VERSION 5.7 ;
  NOWIREEXTENSIONATPIN ON ;
  DIVIDERCHAR "/" ;
  BUSBITCHARS "[]" ;
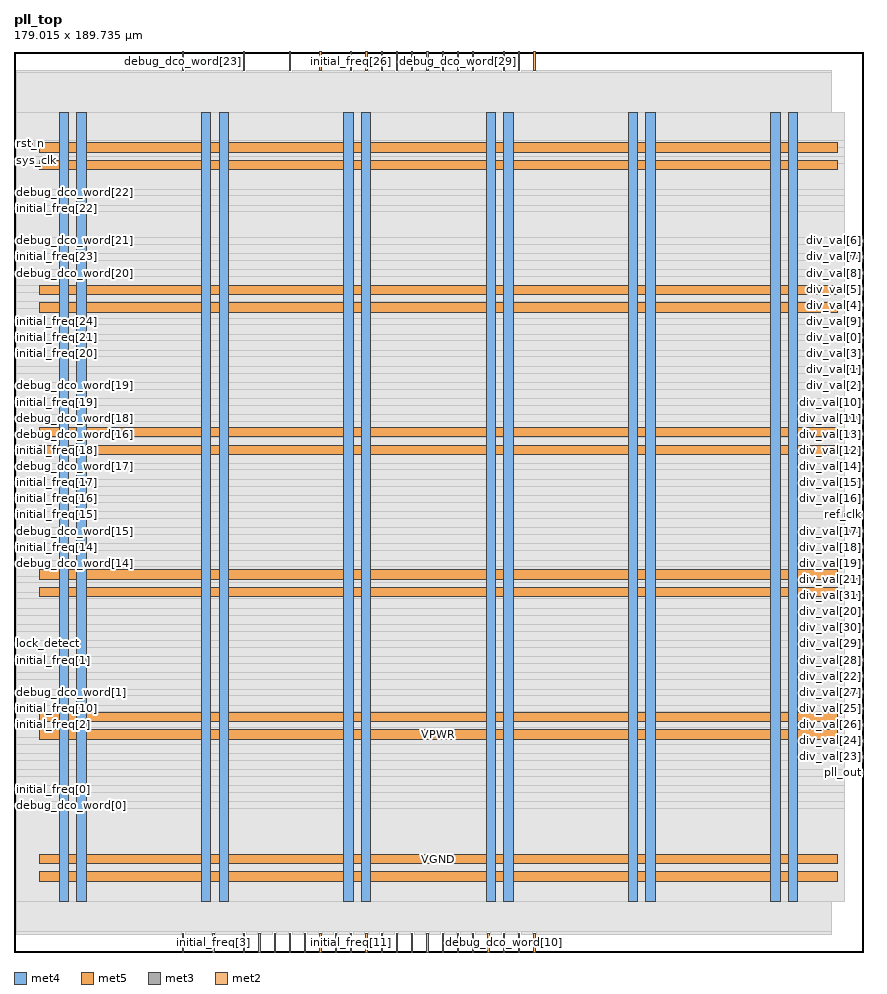
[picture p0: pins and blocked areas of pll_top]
MACRO pll_top
  CLASS BLOCK ;
  FOREIGN pll_top ;
  ORIGIN 0.000 0.000 ;
  SIZE 179.015 BY 189.735 ;
  PIN VGND
    DIRECTION INOUT ;
    USE GROUND ;
    PORT
      LAYER met4 ;
        RECT 13.220 10.640 15.220 177.040 ;
    END
    PORT
      LAYER met4 ;
        RECT 43.220 10.640 45.220 177.040 ;
    END
    PORT
      LAYER met4 ;
        RECT 73.220 10.640 75.220 177.040 ;
    END
    PORT
      LAYER met4 ;
        RECT 103.220 10.640 105.220 177.040 ;
    END
    PORT
      LAYER met4 ;
        RECT 133.220 10.640 135.220 177.040 ;
    END
    PORT
      LAYER met4 ;
        RECT 163.220 10.640 165.220 177.040 ;
    END
    PORT
      LAYER met5 ;
        RECT 5.280 18.580 173.660 20.580 ;
    END
    PORT
      LAYER met5 ;
        RECT 5.280 48.580 173.660 50.580 ;
    END
    PORT
      LAYER met5 ;
        RECT 5.280 78.580 173.660 80.580 ;
    END
    PORT
      LAYER met5 ;
        RECT 5.280 108.580 173.660 110.580 ;
    END
    PORT
      LAYER met5 ;
        RECT 5.280 138.580 173.660 140.580 ;
    END
    PORT
      LAYER met5 ;
        RECT 5.280 168.580 173.660 170.580 ;
    END
  END VGND
  PIN VPWR
    DIRECTION INOUT ;
    USE POWER ;
    PORT
      LAYER met4 ;
        RECT 9.520 10.640 11.520 177.040 ;
    END
    PORT
      LAYER met4 ;
        RECT 39.520 10.640 41.520 177.040 ;
    END
    PORT
      LAYER met4 ;
        RECT 69.520 10.640 71.520 177.040 ;
    END
    PORT
      LAYER met4 ;
        RECT 99.520 10.640 101.520 177.040 ;
    END
    PORT
      LAYER met4 ;
        RECT 129.520 10.640 131.520 177.040 ;
    END
    PORT
      LAYER met4 ;
        RECT 159.520 10.640 161.520 177.040 ;
    END
    PORT
      LAYER met5 ;
        RECT 5.280 14.880 173.660 16.880 ;
    END
    PORT
      LAYER met5 ;
        RECT 5.280 44.880 173.660 46.880 ;
    END
    PORT
      LAYER met5 ;
        RECT 5.280 74.880 173.660 76.880 ;
    END
    PORT
      LAYER met5 ;
        RECT 5.280 104.880 173.660 106.880 ;
    END
    PORT
      LAYER met5 ;
        RECT 5.280 134.880 173.660 136.880 ;
    END
    PORT
      LAYER met5 ;
        RECT 5.280 164.880 173.660 166.880 ;
    END
  END VPWR
  PIN debug_dco_word[0]
    DIRECTION OUTPUT ;
    USE SIGNAL ;
    ANTENNADIFFAREA 0.445500 ;
    PORT
      LAYER met3 ;
        RECT 0.000 30.640 4.000 31.240 ;
    END
  END debug_dco_word[0]
  PIN debug_dco_word[10]
    DIRECTION OUTPUT ;
    USE SIGNAL ;
    ANTENNADIFFAREA 0.445500 ;
    PORT
      LAYER met2 ;
        RECT 103.130 0.000 103.410 4.000 ;
    END
  END debug_dco_word[10]
  PIN debug_dco_word[11]
    DIRECTION OUTPUT ;
    USE SIGNAL ;
    ANTENNADIFFAREA 0.445500 ;
    PORT
      LAYER met2 ;
        RECT 67.710 0.000 67.990 4.000 ;
    END
  END debug_dco_word[11]
  PIN debug_dco_word[12]
    DIRECTION OUTPUT ;
    USE SIGNAL ;
    ANTENNADIFFAREA 0.445500 ;
    PORT
      LAYER met2 ;
        RECT 96.690 0.000 96.970 4.000 ;
    END
  END debug_dco_word[12]
  PIN debug_dco_word[13]
    DIRECTION OUTPUT ;
    USE SIGNAL ;
    ANTENNADIFFAREA 0.445500 ;
    PORT
      LAYER met2 ;
        RECT 87.030 0.000 87.310 4.000 ;
    END
  END debug_dco_word[13]
  PIN debug_dco_word[14]
    DIRECTION OUTPUT ;
    USE SIGNAL ;
    ANTENNADIFFAREA 0.445500 ;
    PORT
      LAYER met3 ;
        RECT 0.000 81.640 4.000 82.240 ;
    END
  END debug_dco_word[14]
  PIN debug_dco_word[15]
    DIRECTION OUTPUT ;
    USE SIGNAL ;
    ANTENNADIFFAREA 0.445500 ;
    PORT
      LAYER met3 ;
        RECT 0.000 88.440 4.000 89.040 ;
    END
  END debug_dco_word[15]
  PIN debug_dco_word[16]
    DIRECTION OUTPUT ;
    USE SIGNAL ;
    ANTENNADIFFAREA 0.445500 ;
    PORT
      LAYER met3 ;
        RECT 0.000 108.840 4.000 109.440 ;
    END
  END debug_dco_word[16]
  PIN debug_dco_word[17]
    DIRECTION OUTPUT ;
    USE SIGNAL ;
    ANTENNADIFFAREA 0.445500 ;
    PORT
      LAYER met3 ;
        RECT 0.000 102.040 4.000 102.640 ;
    END
  END debug_dco_word[17]
  PIN debug_dco_word[18]
    DIRECTION OUTPUT ;
    USE SIGNAL ;
    ANTENNADIFFAREA 0.445500 ;
    PORT
      LAYER met3 ;
        RECT 0.000 112.240 4.000 112.840 ;
    END
  END debug_dco_word[18]
  PIN debug_dco_word[19]
    DIRECTION OUTPUT ;
    USE SIGNAL ;
    ANTENNADIFFAREA 0.445500 ;
    PORT
      LAYER met3 ;
        RECT 0.000 119.040 4.000 119.640 ;
    END
  END debug_dco_word[19]
  PIN debug_dco_word[1]
    DIRECTION OUTPUT ;
    USE SIGNAL ;
    ANTENNADIFFAREA 0.445500 ;
    PORT
      LAYER met3 ;
        RECT 0.000 54.440 4.000 55.040 ;
    END
  END debug_dco_word[1]
  PIN debug_dco_word[20]
    DIRECTION OUTPUT ;
    USE SIGNAL ;
    ANTENNADIFFAREA 0.445500 ;
    PORT
      LAYER met3 ;
        RECT 0.000 142.840 4.000 143.440 ;
    END
  END debug_dco_word[20]
  PIN debug_dco_word[21]
    DIRECTION OUTPUT ;
    USE SIGNAL ;
    ANTENNADIFFAREA 0.445500 ;
    PORT
      LAYER met3 ;
        RECT 0.000 149.640 4.000 150.240 ;
    END
  END debug_dco_word[21]
  PIN debug_dco_word[22]
    DIRECTION OUTPUT ;
    USE SIGNAL ;
    ANTENNADIFFAREA 0.445500 ;
    PORT
      LAYER met3 ;
        RECT 0.000 159.840 4.000 160.440 ;
    END
  END debug_dco_word[22]
  PIN debug_dco_word[23]
    DIRECTION OUTPUT ;
    USE SIGNAL ;
    ANTENNADIFFAREA 0.445500 ;
    PORT
      LAYER met2 ;
        RECT 35.510 185.735 35.790 189.735 ;
    END
  END debug_dco_word[23]
  PIN debug_dco_word[24]
    DIRECTION OUTPUT ;
    USE SIGNAL ;
    ANTENNADIFFAREA 0.445500 ;
    PORT
      LAYER met2 ;
        RECT 48.390 185.735 48.670 189.735 ;
    END
  END debug_dco_word[24]
  PIN debug_dco_word[25]
    DIRECTION OUTPUT ;
    USE SIGNAL ;
    ANTENNADIFFAREA 0.445500 ;
    PORT
      LAYER met2 ;
        RECT 64.490 185.735 64.770 189.735 ;
    END
  END debug_dco_word[25]
  PIN debug_dco_word[26]
    DIRECTION OUTPUT ;
    USE SIGNAL ;
    ANTENNADIFFAREA 0.445500 ;
    PORT
      LAYER met2 ;
        RECT 77.370 185.735 77.650 189.735 ;
    END
  END debug_dco_word[26]
  PIN debug_dco_word[27]
    DIRECTION OUTPUT ;
    USE SIGNAL ;
    ANTENNADIFFAREA 0.445500 ;
    PORT
      LAYER met2 ;
        RECT 80.590 185.735 80.870 189.735 ;
    END
  END debug_dco_word[27]
  PIN debug_dco_word[28]
    DIRECTION OUTPUT ;
    USE SIGNAL ;
    ANTENNADIFFAREA 0.445500 ;
    PORT
      LAYER met2 ;
        RECT 90.250 185.735 90.530 189.735 ;
    END
  END debug_dco_word[28]
  PIN debug_dco_word[29]
    DIRECTION OUTPUT ;
    USE SIGNAL ;
    ANTENNADIFFAREA 0.445500 ;
    PORT
      LAYER met2 ;
        RECT 93.470 185.735 93.750 189.735 ;
    END
  END debug_dco_word[29]
  PIN debug_dco_word[2]
    DIRECTION OUTPUT ;
    USE SIGNAL ;
    ANTENNADIFFAREA 0.445500 ;
    PORT
      LAYER met2 ;
        RECT 35.510 0.000 35.790 4.000 ;
    END
  END debug_dco_word[2]
  PIN debug_dco_word[30]
    DIRECTION OUTPUT ;
    USE SIGNAL ;
    ANTENNADIFFAREA 0.445500 ;
    PORT
      LAYER met2 ;
        RECT 106.350 185.735 106.630 189.735 ;
    END
  END debug_dco_word[30]
  PIN debug_dco_word[31]
    DIRECTION OUTPUT ;
    USE SIGNAL ;
    ANTENNADIFFAREA 0.445500 ;
    PORT
      LAYER met2 ;
        RECT 109.570 185.735 109.850 189.735 ;
    END
  END debug_dco_word[31]
  PIN debug_dco_word[3]
    DIRECTION OUTPUT ;
    USE SIGNAL ;
    ANTENNADIFFAREA 0.445500 ;
    PORT
      LAYER met2 ;
        RECT 48.390 0.000 48.670 4.000 ;
    END
  END debug_dco_word[3]
  PIN debug_dco_word[4]
    DIRECTION OUTPUT ;
    USE SIGNAL ;
    ANTENNADIFFAREA 0.445500 ;
    PORT
      LAYER met2 ;
        RECT 51.610 0.000 51.890 4.000 ;
    END
  END debug_dco_word[4]
  PIN debug_dco_word[5]
    DIRECTION OUTPUT ;
    USE SIGNAL ;
    ANTENNADIFFAREA 0.445500 ;
    PORT
      LAYER met2 ;
        RECT 61.270 0.000 61.550 4.000 ;
    END
  END debug_dco_word[5]
  PIN debug_dco_word[6]
    DIRECTION OUTPUT ;
    USE SIGNAL ;
    ANTENNADIFFAREA 0.445500 ;
    PORT
      LAYER met2 ;
        RECT 90.250 0.000 90.530 4.000 ;
    END
  END debug_dco_word[6]
  PIN debug_dco_word[7]
    DIRECTION OUTPUT ;
    USE SIGNAL ;
    ANTENNADIFFAREA 0.445500 ;
    PORT
      LAYER met2 ;
        RECT 109.570 0.000 109.850 4.000 ;
    END
  END debug_dco_word[7]
  PIN debug_dco_word[8]
    DIRECTION OUTPUT ;
    USE SIGNAL ;
    ANTENNADIFFAREA 0.445500 ;
    PORT
      LAYER met2 ;
        RECT 99.910 0.000 100.190 4.000 ;
    END
  END debug_dco_word[8]
  PIN debug_dco_word[9]
    DIRECTION OUTPUT ;
    USE SIGNAL ;
    ANTENNADIFFAREA 0.445500 ;
    PORT
      LAYER met2 ;
        RECT 106.350 0.000 106.630 4.000 ;
    END
  END debug_dco_word[9]
  PIN div_val[0]
    DIRECTION INPUT ;
    USE SIGNAL ;
    ANTENNAGATEAREA 0.126000 ;
    PORT
      LAYER met3 ;
        RECT 175.015 129.240 179.015 129.840 ;
    END
  END div_val[0]
  PIN div_val[10]
    DIRECTION INPUT ;
    USE SIGNAL ;
    ANTENNAGATEAREA 0.126000 ;
    PORT
      LAYER met3 ;
        RECT 175.015 115.640 179.015 116.240 ;
    END
  END div_val[10]
  PIN div_val[11]
    DIRECTION INPUT ;
    USE SIGNAL ;
    ANTENNAGATEAREA 0.126000 ;
    PORT
      LAYER met3 ;
        RECT 175.015 112.240 179.015 112.840 ;
    END
  END div_val[11]
  PIN div_val[12]
    DIRECTION INPUT ;
    USE SIGNAL ;
    ANTENNAGATEAREA 0.196500 ;
    PORT
      LAYER met3 ;
        RECT 175.015 105.440 179.015 106.040 ;
    END
  END div_val[12]
  PIN div_val[13]
    DIRECTION INPUT ;
    USE SIGNAL ;
    ANTENNAGATEAREA 0.126000 ;
    PORT
      LAYER met3 ;
        RECT 175.015 108.840 179.015 109.440 ;
    END
  END div_val[13]
  PIN div_val[14]
    DIRECTION INPUT ;
    USE SIGNAL ;
    ANTENNAGATEAREA 0.126000 ;
    PORT
      LAYER met3 ;
        RECT 175.015 102.040 179.015 102.640 ;
    END
  END div_val[14]
  PIN div_val[15]
    DIRECTION INPUT ;
    USE SIGNAL ;
    ANTENNAGATEAREA 0.196500 ;
    PORT
      LAYER met3 ;
        RECT 175.015 98.640 179.015 99.240 ;
    END
  END div_val[15]
  PIN div_val[16]
    DIRECTION INPUT ;
    USE SIGNAL ;
    ANTENNAGATEAREA 0.213000 ;
    PORT
      LAYER met3 ;
        RECT 175.015 95.240 179.015 95.840 ;
    END
  END div_val[16]
  PIN div_val[17]
    DIRECTION INPUT ;
    USE SIGNAL ;
    ANTENNAGATEAREA 0.196500 ;
    PORT
      LAYER met3 ;
        RECT 175.015 88.440 179.015 89.040 ;
    END
  END div_val[17]
  PIN div_val[18]
    DIRECTION INPUT ;
    USE SIGNAL ;
    ANTENNAGATEAREA 0.196500 ;
    PORT
      LAYER met3 ;
        RECT 175.015 85.040 179.015 85.640 ;
    END
  END div_val[18]
  PIN div_val[19]
    DIRECTION INPUT ;
    USE SIGNAL ;
    ANTENNAGATEAREA 0.196500 ;
    PORT
      LAYER met3 ;
        RECT 175.015 81.640 179.015 82.240 ;
    END
  END div_val[19]
  PIN div_val[1]
    DIRECTION INPUT ;
    USE SIGNAL ;
    ANTENNAGATEAREA 0.126000 ;
    PORT
      LAYER met3 ;
        RECT 175.015 122.440 179.015 123.040 ;
    END
  END div_val[1]
  PIN div_val[20]
    DIRECTION INPUT ;
    USE SIGNAL ;
    ANTENNAGATEAREA 0.196500 ;
    PORT
      LAYER met3 ;
        RECT 175.015 71.440 179.015 72.040 ;
    END
  END div_val[20]
  PIN div_val[21]
    DIRECTION INPUT ;
    USE SIGNAL ;
    ANTENNAGATEAREA 0.196500 ;
    PORT
      LAYER met3 ;
        RECT 175.015 78.240 179.015 78.840 ;
    END
  END div_val[21]
  PIN div_val[22]
    DIRECTION INPUT ;
    USE SIGNAL ;
    ANTENNAGATEAREA 0.126000 ;
    PORT
      LAYER met3 ;
        RECT 175.015 57.840 179.015 58.440 ;
    END
  END div_val[22]
  PIN div_val[23]
    DIRECTION INPUT ;
    USE SIGNAL ;
    ANTENNAGATEAREA 0.126000 ;
    PORT
      LAYER met3 ;
        RECT 175.015 40.840 179.015 41.440 ;
    END
  END div_val[23]
  PIN div_val[24]
    DIRECTION INPUT ;
    USE SIGNAL ;
    ANTENNAGATEAREA 0.196500 ;
    PORT
      LAYER met3 ;
        RECT 175.015 44.240 179.015 44.840 ;
    END
  END div_val[24]
  PIN div_val[25]
    DIRECTION INPUT ;
    USE SIGNAL ;
    ANTENNAGATEAREA 0.126000 ;
    PORT
      LAYER met3 ;
        RECT 175.015 51.040 179.015 51.640 ;
    END
  END div_val[25]
  PIN div_val[26]
    DIRECTION INPUT ;
    USE SIGNAL ;
    ANTENNAGATEAREA 0.126000 ;
    PORT
      LAYER met3 ;
        RECT 175.015 47.640 179.015 48.240 ;
    END
  END div_val[26]
  PIN div_val[27]
    DIRECTION INPUT ;
    USE SIGNAL ;
    ANTENNAGATEAREA 0.196500 ;
    PORT
      LAYER met3 ;
        RECT 175.015 54.440 179.015 55.040 ;
    END
  END div_val[27]
  PIN div_val[28]
    DIRECTION INPUT ;
    USE SIGNAL ;
    ANTENNAGATEAREA 0.213000 ;
    PORT
      LAYER met3 ;
        RECT 175.015 61.240 179.015 61.840 ;
    END
  END div_val[28]
  PIN div_val[29]
    DIRECTION INPUT ;
    USE SIGNAL ;
    ANTENNAGATEAREA 0.126000 ;
    PORT
      LAYER met3 ;
        RECT 175.015 64.640 179.015 65.240 ;
    END
  END div_val[29]
  PIN div_val[2]
    DIRECTION INPUT ;
    USE SIGNAL ;
    ANTENNAGATEAREA 0.126000 ;
    PORT
      LAYER met3 ;
        RECT 175.015 119.040 179.015 119.640 ;
    END
  END div_val[2]
  PIN div_val[30]
    DIRECTION INPUT ;
    USE SIGNAL ;
    ANTENNAGATEAREA 0.196500 ;
    PORT
      LAYER met3 ;
        RECT 175.015 68.040 179.015 68.640 ;
    END
  END div_val[30]
  PIN div_val[31]
    DIRECTION INPUT ;
    USE SIGNAL ;
    ANTENNAGATEAREA 0.196500 ;
    PORT
      LAYER met3 ;
        RECT 175.015 74.840 179.015 75.440 ;
    END
  END div_val[31]
  PIN div_val[3]
    DIRECTION INPUT ;
    USE SIGNAL ;
    ANTENNAGATEAREA 0.196500 ;
    PORT
      LAYER met3 ;
        RECT 175.015 125.840 179.015 126.440 ;
    END
  END div_val[3]
  PIN div_val[4]
    DIRECTION INPUT ;
    USE SIGNAL ;
    ANTENNAGATEAREA 0.213000 ;
    PORT
      LAYER met3 ;
        RECT 175.015 136.040 179.015 136.640 ;
    END
  END div_val[4]
  PIN div_val[5]
    DIRECTION INPUT ;
    USE SIGNAL ;
    ANTENNAGATEAREA 0.126000 ;
    PORT
      LAYER met3 ;
        RECT 175.015 139.440 179.015 140.040 ;
    END
  END div_val[5]
  PIN div_val[6]
    DIRECTION INPUT ;
    USE SIGNAL ;
    ANTENNAGATEAREA 0.196500 ;
    PORT
      LAYER met3 ;
        RECT 175.015 149.640 179.015 150.240 ;
    END
  END div_val[6]
  PIN div_val[7]
    DIRECTION INPUT ;
    USE SIGNAL ;
    ANTENNAGATEAREA 0.213000 ;
    PORT
      LAYER met3 ;
        RECT 175.015 146.240 179.015 146.840 ;
    END
  END div_val[7]
  PIN div_val[8]
    DIRECTION INPUT ;
    USE SIGNAL ;
    ANTENNAGATEAREA 0.213000 ;
    PORT
      LAYER met3 ;
        RECT 175.015 142.840 179.015 143.440 ;
    END
  END div_val[8]
  PIN div_val[9]
    DIRECTION INPUT ;
    USE SIGNAL ;
    ANTENNAGATEAREA 0.196500 ;
    PORT
      LAYER met3 ;
        RECT 175.015 132.640 179.015 133.240 ;
    END
  END div_val[9]
  PIN initial_freq[0]
    DIRECTION INPUT ;
    USE SIGNAL ;
    ANTENNAGATEAREA 0.196500 ;
    PORT
      LAYER met3 ;
        RECT 0.000 34.040 4.000 34.640 ;
    END
  END initial_freq[0]
  PIN initial_freq[10]
    DIRECTION INPUT ;
    USE SIGNAL ;
    ANTENNAGATEAREA 0.196500 ;
    PORT
      LAYER met3 ;
        RECT 0.000 51.040 4.000 51.640 ;
    END
  END initial_freq[10]
  PIN initial_freq[11]
    DIRECTION INPUT ;
    USE SIGNAL ;
    ANTENNAGATEAREA 0.196500 ;
    PORT
      LAYER met2 ;
        RECT 70.930 0.000 71.210 4.000 ;
    END
  END initial_freq[11]
  PIN initial_freq[12]
    DIRECTION INPUT ;
    USE SIGNAL ;
    ANTENNAGATEAREA 0.196500 ;
    PORT
      LAYER met2 ;
        RECT 74.150 0.000 74.430 4.000 ;
    END
  END initial_freq[12]
  PIN initial_freq[13]
    DIRECTION INPUT ;
    USE SIGNAL ;
    ANTENNAGATEAREA 0.196500 ;
    PORT
      LAYER met2 ;
        RECT 77.370 0.000 77.650 4.000 ;
    END
  END initial_freq[13]
  PIN initial_freq[14]
    DIRECTION INPUT ;
    USE SIGNAL ;
    ANTENNAGATEAREA 0.196500 ;
    PORT
      LAYER met3 ;
        RECT 0.000 85.040 4.000 85.640 ;
    END
  END initial_freq[14]
  PIN initial_freq[15]
    DIRECTION INPUT ;
    USE SIGNAL ;
    ANTENNAGATEAREA 0.196500 ;
    PORT
      LAYER met3 ;
        RECT 0.000 91.840 4.000 92.440 ;
    END
  END initial_freq[15]
  PIN initial_freq[16]
    DIRECTION INPUT ;
    USE SIGNAL ;
    ANTENNAGATEAREA 0.196500 ;
    PORT
      LAYER met3 ;
        RECT 0.000 95.240 4.000 95.840 ;
    END
  END initial_freq[16]
  PIN initial_freq[17]
    DIRECTION INPUT ;
    USE SIGNAL ;
    ANTENNAGATEAREA 0.196500 ;
    PORT
      LAYER met3 ;
        RECT 0.000 98.640 4.000 99.240 ;
    END
  END initial_freq[17]
  PIN initial_freq[18]
    DIRECTION INPUT ;
    USE SIGNAL ;
    ANTENNAGATEAREA 0.196500 ;
    PORT
      LAYER met3 ;
        RECT 0.000 105.440 4.000 106.040 ;
    END
  END initial_freq[18]
  PIN initial_freq[19]
    DIRECTION INPUT ;
    USE SIGNAL ;
    ANTENNAGATEAREA 0.196500 ;
    PORT
      LAYER met3 ;
        RECT 0.000 115.640 4.000 116.240 ;
    END
  END initial_freq[19]
  PIN initial_freq[1]
    DIRECTION INPUT ;
    USE SIGNAL ;
    ANTENNAGATEAREA 0.196500 ;
    PORT
      LAYER met3 ;
        RECT 0.000 61.240 4.000 61.840 ;
    END
  END initial_freq[1]
  PIN initial_freq[20]
    DIRECTION INPUT ;
    USE SIGNAL ;
    ANTENNAGATEAREA 0.196500 ;
    PORT
      LAYER met3 ;
        RECT 0.000 125.840 4.000 126.440 ;
    END
  END initial_freq[20]
  PIN initial_freq[21]
    DIRECTION INPUT ;
    USE SIGNAL ;
    ANTENNAGATEAREA 0.196500 ;
    PORT
      LAYER met3 ;
        RECT 0.000 129.240 4.000 129.840 ;
    END
  END initial_freq[21]
  PIN initial_freq[22]
    DIRECTION INPUT ;
    USE SIGNAL ;
    ANTENNAGATEAREA 0.196500 ;
    PORT
      LAYER met3 ;
        RECT 0.000 156.440 4.000 157.040 ;
    END
  END initial_freq[22]
  PIN initial_freq[23]
    DIRECTION INPUT ;
    USE SIGNAL ;
    ANTENNAGATEAREA 0.196500 ;
    PORT
      LAYER met3 ;
        RECT 0.000 146.240 4.000 146.840 ;
    END
  END initial_freq[23]
  PIN initial_freq[24]
    DIRECTION INPUT ;
    USE SIGNAL ;
    ANTENNAGATEAREA 0.196500 ;
    PORT
      LAYER met3 ;
        RECT 0.000 132.640 4.000 133.240 ;
    END
  END initial_freq[24]
  PIN initial_freq[25]
    DIRECTION INPUT ;
    USE SIGNAL ;
    ANTENNAGATEAREA 0.196500 ;
    PORT
      LAYER met2 ;
        RECT 58.050 185.735 58.330 189.735 ;
    END
  END initial_freq[25]
  PIN initial_freq[26]
    DIRECTION INPUT ;
    USE SIGNAL ;
    ANTENNAGATEAREA 0.196500 ;
    PORT
      LAYER met2 ;
        RECT 70.930 185.735 71.210 189.735 ;
    END
  END initial_freq[26]
  PIN initial_freq[27]
    DIRECTION INPUT ;
    USE SIGNAL ;
    ANTENNAGATEAREA 0.196500 ;
    PORT
      LAYER met2 ;
        RECT 74.150 185.735 74.430 189.735 ;
    END
  END initial_freq[27]
  PIN initial_freq[28]
    DIRECTION INPUT ;
    USE SIGNAL ;
    ANTENNAGATEAREA 0.196500 ;
    PORT
      LAYER met2 ;
        RECT 83.810 185.735 84.090 189.735 ;
    END
  END initial_freq[28]
  PIN initial_freq[29]
    DIRECTION INPUT ;
    USE SIGNAL ;
    ANTENNAGATEAREA 0.196500 ;
    PORT
      LAYER met2 ;
        RECT 87.030 185.735 87.310 189.735 ;
    END
  END initial_freq[29]
  PIN initial_freq[2]
    DIRECTION INPUT ;
    USE SIGNAL ;
    ANTENNAGATEAREA 0.196500 ;
    PORT
      LAYER met3 ;
        RECT 0.000 47.640 4.000 48.240 ;
    END
  END initial_freq[2]
  PIN initial_freq[30]
    DIRECTION INPUT ;
    USE SIGNAL ;
    ANTENNAGATEAREA 0.196500 ;
    PORT
      LAYER met2 ;
        RECT 96.690 185.735 96.970 189.735 ;
    END
  END initial_freq[30]
  PIN initial_freq[31]
    DIRECTION INPUT ;
    USE SIGNAL ;
    ANTENNAGATEAREA 0.196500 ;
    PORT
      LAYER met2 ;
        RECT 103.130 185.735 103.410 189.735 ;
    END
  END initial_freq[31]
  PIN initial_freq[3]
    DIRECTION INPUT ;
    USE SIGNAL ;
    ANTENNAGATEAREA 0.196500 ;
    PORT
      LAYER met2 ;
        RECT 41.950 0.000 42.230 4.000 ;
    END
  END initial_freq[3]
  PIN initial_freq[4]
    DIRECTION INPUT ;
    USE SIGNAL ;
    ANTENNAGATEAREA 0.196500 ;
    PORT
      LAYER met2 ;
        RECT 54.830 0.000 55.110 4.000 ;
    END
  END initial_freq[4]
  PIN initial_freq[5]
    DIRECTION INPUT ;
    USE SIGNAL ;
    ANTENNAGATEAREA 0.196500 ;
    PORT
      LAYER met2 ;
        RECT 64.490 0.000 64.770 4.000 ;
    END
  END initial_freq[5]
  PIN initial_freq[6]
    DIRECTION INPUT ;
    USE SIGNAL ;
    ANTENNAGATEAREA 0.196500 ;
    PORT
      LAYER met2 ;
        RECT 80.590 0.000 80.870 4.000 ;
    END
  END initial_freq[6]
  PIN initial_freq[7]
    DIRECTION INPUT ;
    USE SIGNAL ;
    ANTENNAGATEAREA 0.196500 ;
    PORT
      LAYER met2 ;
        RECT 93.470 0.000 93.750 4.000 ;
    END
  END initial_freq[7]
  PIN initial_freq[8]
    DIRECTION INPUT ;
    USE SIGNAL ;
    ANTENNAGATEAREA 0.196500 ;
    PORT
      LAYER met2 ;
        RECT 83.810 0.000 84.090 4.000 ;
    END
  END initial_freq[8]
  PIN initial_freq[9]
    DIRECTION INPUT ;
    USE SIGNAL ;
    ANTENNAGATEAREA 0.196500 ;
    PORT
      LAYER met2 ;
        RECT 58.050 0.000 58.330 4.000 ;
    END
  END initial_freq[9]
  PIN lock_detect
    DIRECTION OUTPUT ;
    USE SIGNAL ;
    ANTENNADIFFAREA 0.445500 ;
    PORT
      LAYER met3 ;
        RECT 0.000 64.640 4.000 65.240 ;
    END
  END lock_detect
  PIN pll_out
    DIRECTION OUTPUT ;
    USE SIGNAL ;
    ANTENNADIFFAREA 0.445500 ;
    PORT
      LAYER met3 ;
        RECT 175.015 37.440 179.015 38.040 ;
    END
  END pll_out
  PIN ref_clk
    DIRECTION INPUT ;
    USE SIGNAL ;
    ANTENNAGATEAREA 0.196500 ;
    PORT
      LAYER met3 ;
        RECT 175.015 91.840 179.015 92.440 ;
    END
  END ref_clk
  PIN rst_n
    DIRECTION INPUT ;
    USE SIGNAL ;
    ANTENNAGATEAREA 0.196500 ;
    PORT
      LAYER met3 ;
        RECT 0.000 170.040 4.000 170.640 ;
    END
  END rst_n
  PIN sys_clk
    DIRECTION INPUT ;
    USE SIGNAL ;
    ANTENNAGATEAREA 0.852000 ;
    PORT
      LAYER met3 ;
        RECT 0.000 166.640 4.000 167.240 ;
    END
  END sys_clk
  OBS
      LAYER nwell ;
        RECT 5.330 10.795 173.610 176.990 ;
      LAYER li1 ;
        RECT 5.520 10.795 173.420 176.885 ;
      LAYER met1 ;
        RECT 0.530 10.640 173.420 177.040 ;
      LAYER met2 ;
        RECT 0.550 185.455 35.230 185.735 ;
        RECT 36.070 185.455 48.110 185.735 ;
        RECT 48.950 185.455 57.770 185.735 ;
        RECT 58.610 185.455 64.210 185.735 ;
        RECT 65.050 185.455 70.650 185.735 ;
        RECT 71.490 185.455 73.870 185.735 ;
        RECT 74.710 185.455 77.090 185.735 ;
        RECT 77.930 185.455 80.310 185.735 ;
        RECT 81.150 185.455 83.530 185.735 ;
        RECT 84.370 185.455 86.750 185.735 ;
        RECT 87.590 185.455 89.970 185.735 ;
        RECT 90.810 185.455 93.190 185.735 ;
        RECT 94.030 185.455 96.410 185.735 ;
        RECT 97.250 185.455 102.850 185.735 ;
        RECT 103.690 185.455 106.070 185.735 ;
        RECT 106.910 185.455 109.290 185.735 ;
        RECT 110.130 185.455 172.400 185.735 ;
        RECT 0.550 4.280 172.400 185.455 ;
        RECT 0.550 3.670 35.230 4.280 ;
        RECT 36.070 3.670 41.670 4.280 ;
        RECT 42.510 3.670 48.110 4.280 ;
        RECT 48.950 3.670 51.330 4.280 ;
        RECT 52.170 3.670 54.550 4.280 ;
        RECT 55.390 3.670 57.770 4.280 ;
        RECT 58.610 3.670 60.990 4.280 ;
        RECT 61.830 3.670 64.210 4.280 ;
        RECT 65.050 3.670 67.430 4.280 ;
        RECT 68.270 3.670 70.650 4.280 ;
        RECT 71.490 3.670 73.870 4.280 ;
        RECT 74.710 3.670 77.090 4.280 ;
        RECT 77.930 3.670 80.310 4.280 ;
        RECT 81.150 3.670 83.530 4.280 ;
        RECT 84.370 3.670 86.750 4.280 ;
        RECT 87.590 3.670 89.970 4.280 ;
        RECT 90.810 3.670 93.190 4.280 ;
        RECT 94.030 3.670 96.410 4.280 ;
        RECT 97.250 3.670 99.630 4.280 ;
        RECT 100.470 3.670 102.850 4.280 ;
        RECT 103.690 3.670 106.070 4.280 ;
        RECT 106.910 3.670 109.290 4.280 ;
        RECT 110.130 3.670 172.400 4.280 ;
      LAYER met3 ;
        RECT 0.525 171.040 175.015 176.965 ;
        RECT 4.400 169.640 175.015 171.040 ;
        RECT 0.525 167.640 175.015 169.640 ;
        RECT 4.400 166.240 175.015 167.640 ;
        RECT 0.525 160.840 175.015 166.240 ;
        RECT 4.400 159.440 175.015 160.840 ;
        RECT 0.525 157.440 175.015 159.440 ;
        RECT 4.400 156.040 175.015 157.440 ;
        RECT 0.525 150.640 175.015 156.040 ;
        RECT 4.400 149.240 174.615 150.640 ;
        RECT 0.525 147.240 175.015 149.240 ;
        RECT 4.400 145.840 174.615 147.240 ;
        RECT 0.525 143.840 175.015 145.840 ;
        RECT 4.400 142.440 174.615 143.840 ;
        RECT 0.525 140.440 175.015 142.440 ;
        RECT 0.525 139.040 174.615 140.440 ;
        RECT 0.525 137.040 175.015 139.040 ;
        RECT 0.525 135.640 174.615 137.040 ;
        RECT 0.525 133.640 175.015 135.640 ;
        RECT 4.400 132.240 174.615 133.640 ;
        RECT 0.525 130.240 175.015 132.240 ;
        RECT 4.400 128.840 174.615 130.240 ;
        RECT 0.525 126.840 175.015 128.840 ;
        RECT 4.400 125.440 174.615 126.840 ;
        RECT 0.525 123.440 175.015 125.440 ;
        RECT 0.525 122.040 174.615 123.440 ;
        RECT 0.525 120.040 175.015 122.040 ;
        RECT 4.400 118.640 174.615 120.040 ;
        RECT 0.525 116.640 175.015 118.640 ;
        RECT 4.400 115.240 174.615 116.640 ;
        RECT 0.525 113.240 175.015 115.240 ;
        RECT 4.400 111.840 174.615 113.240 ;
        RECT 0.525 109.840 175.015 111.840 ;
        RECT 4.400 108.440 174.615 109.840 ;
        RECT 0.525 106.440 175.015 108.440 ;
        RECT 4.400 105.040 174.615 106.440 ;
        RECT 0.525 103.040 175.015 105.040 ;
        RECT 4.400 101.640 174.615 103.040 ;
        RECT 0.525 99.640 175.015 101.640 ;
        RECT 4.400 98.240 174.615 99.640 ;
        RECT 0.525 96.240 175.015 98.240 ;
        RECT 4.400 94.840 174.615 96.240 ;
        RECT 0.525 92.840 175.015 94.840 ;
        RECT 4.400 91.440 174.615 92.840 ;
        RECT 0.525 89.440 175.015 91.440 ;
        RECT 4.400 88.040 174.615 89.440 ;
        RECT 0.525 86.040 175.015 88.040 ;
        RECT 4.400 84.640 174.615 86.040 ;
        RECT 0.525 82.640 175.015 84.640 ;
        RECT 4.400 81.240 174.615 82.640 ;
        RECT 0.525 79.240 175.015 81.240 ;
        RECT 0.525 77.840 174.615 79.240 ;
        RECT 0.525 75.840 175.015 77.840 ;
        RECT 0.525 74.440 174.615 75.840 ;
        RECT 0.525 72.440 175.015 74.440 ;
        RECT 0.525 71.040 174.615 72.440 ;
        RECT 0.525 69.040 175.015 71.040 ;
        RECT 0.525 67.640 174.615 69.040 ;
        RECT 0.525 65.640 175.015 67.640 ;
        RECT 4.400 64.240 174.615 65.640 ;
        RECT 0.525 62.240 175.015 64.240 ;
        RECT 4.400 60.840 174.615 62.240 ;
        RECT 0.525 58.840 175.015 60.840 ;
        RECT 0.525 57.440 174.615 58.840 ;
        RECT 0.525 55.440 175.015 57.440 ;
        RECT 4.400 54.040 174.615 55.440 ;
        RECT 0.525 52.040 175.015 54.040 ;
        RECT 4.400 50.640 174.615 52.040 ;
        RECT 0.525 48.640 175.015 50.640 ;
        RECT 4.400 47.240 174.615 48.640 ;
        RECT 0.525 45.240 175.015 47.240 ;
        RECT 0.525 43.840 174.615 45.240 ;
        RECT 0.525 41.840 175.015 43.840 ;
        RECT 0.525 40.440 174.615 41.840 ;
        RECT 0.525 38.440 175.015 40.440 ;
        RECT 0.525 37.040 174.615 38.440 ;
        RECT 0.525 35.040 175.015 37.040 ;
        RECT 4.400 33.640 175.015 35.040 ;
        RECT 0.525 31.640 175.015 33.640 ;
        RECT 4.400 30.240 175.015 31.640 ;
        RECT 0.525 10.715 175.015 30.240 ;
  END
END pll_top
END LIBRARY

